One B-rep face of a CAD part: STEP entity #1071.
In plain terms, the planar face has unit normal (1, 0, 0).
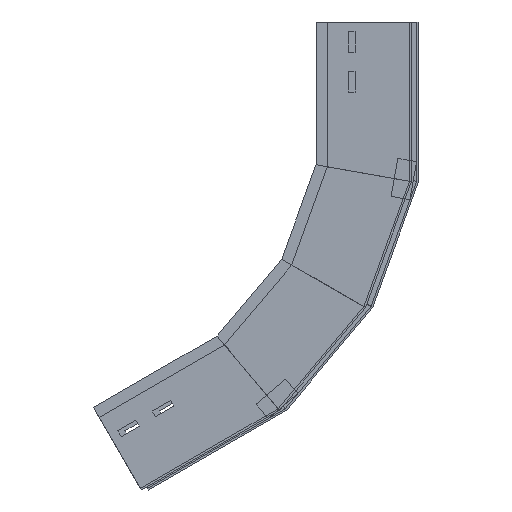
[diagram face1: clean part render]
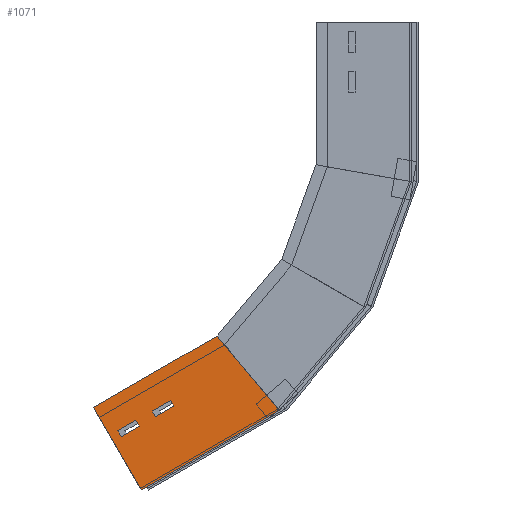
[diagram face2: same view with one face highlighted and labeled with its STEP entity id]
Its self-contained STEP definition (entity closure, numbers rounded to 3 decimals):
#58 = DIRECTION ( 'NONE',  ( 0., 1., 0. ) ) ;
#89 = VERTEX_POINT ( 'NONE', #1633 ) ;
#90 = CARTESIAN_POINT ( 'NONE',  ( 0., 59., -51.505 ) ) ;
#111 = CARTESIAN_POINT ( 'NONE',  ( 0., 59., -51.505 ) ) ;
#126 = CARTESIAN_POINT ( 'NONE',  ( 0., 59., -9.835 ) ) ;
#133 = VECTOR ( 'NONE', #388, 1000. ) ;
#162 = VERTEX_POINT ( 'NONE', #1495 ) ;
#174 = VERTEX_POINT ( 'NONE', #453 ) ;
#176 = EDGE_LOOP ( 'NONE', ( #567, #268, #1676, #1241 ) ) ;
#184 = VERTEX_POINT ( 'NONE', #717 ) ;
#206 = EDGE_CURVE ( 'NONE', #1659, #1650, #1107, .T. ) ;
#216 = CARTESIAN_POINT ( 'NONE',  ( 0., 28.627, -162.352 ) ) ;
#221 = ORIENTED_EDGE ( 'NONE', *, *, #1467, .T. ) ;
#244 = VECTOR ( 'NONE', #1337, 1000. ) ;
#251 = LINE ( 'NONE', #1556, #1500 ) ;
#258 = FACE_OUTER_BOUND ( 'NONE', #339, .T. ) ;
#267 = EDGE_CURVE ( 'NONE', #1477, #358, #1668, .T. ) ;
#268 = ORIENTED_EDGE ( 'NONE', *, *, #1410, .T. ) ;
#337 = EDGE_CURVE ( 'NONE', #184, #162, #1294, .T. ) ;
#339 = EDGE_LOOP ( 'NONE', ( #470, #1189, #221, #1210 ) ) ;
#345 = VECTOR ( 'NONE', #1343, 1000. ) ;
#354 = PLANE ( 'NONE',  #686 ) ;
#356 = CARTESIAN_POINT ( 'NONE',  ( 0., 100., -149.767 ) ) ;
#358 = VERTEX_POINT ( 'NONE', #111 ) ;
#363 = EDGE_CURVE ( 'NONE', #1205, #174, #1523, .T. ) ;
#369 = DIRECTION ( 'NONE',  ( 0., 0., -1. ) ) ;
#388 = DIRECTION ( 'NONE',  ( 0., 0., 1. ) ) ;
#426 = CARTESIAN_POINT ( 'NONE',  ( 0., 66., -51.505 ) ) ;
#453 = CARTESIAN_POINT ( 'NONE',  ( 0., 66., -31.835 ) ) ;
#470 = ORIENTED_EDGE ( 'NONE', *, *, #1238, .F. ) ;
#502 = LINE ( 'NONE', #905, #1010 ) ;
#567 = ORIENTED_EDGE ( 'NONE', *, *, #1621, .T. ) ;
#577 = VECTOR ( 'NONE', #369, 1000. ) ;
#632 = FACE_BOUND ( 'NONE', #176, .T. ) ;
#637 = DIRECTION ( 'NONE',  ( 0., 0., -1. ) ) ;
#643 = CARTESIAN_POINT ( 'NONE',  ( 0., 0., 0. ) ) ;
#651 = CARTESIAN_POINT ( 'NONE',  ( 0., 100., 0. ) ) ;
#663 = DIRECTION ( 'NONE',  ( 0., 1., 0. ) ) ;
#686 = AXIS2_PLACEMENT_3D ( 'NONE', #1536, #893, #1386 ) ;
#717 = CARTESIAN_POINT ( 'NONE',  ( 0., 59., -31.835 ) ) ;
#735 = DIRECTION ( 'NONE',  ( 0., -0.985, -0.174 ) ) ;
#771 = VERTEX_POINT ( 'NONE', #1468 ) ;
#775 = LINE ( 'NONE', #1673, #577 ) ;
#796 = EDGE_CURVE ( 'NONE', #162, #1205, #1585, .T. ) ;
#826 = CARTESIAN_POINT ( 'NONE',  ( 0., 66., -51.505 ) ) ;
#831 = LINE ( 'NONE', #826, #244 ) ;
#893 = DIRECTION ( 'NONE',  ( -1., 0., 0. ) ) ;
#897 = VECTOR ( 'NONE', #1159, 1000. ) ;
#905 = CARTESIAN_POINT ( 'NONE',  ( 0., 66., -73.505 ) ) ;
#921 = CARTESIAN_POINT ( 'NONE',  ( 0., 66., -31.835 ) ) ;
#973 = CARTESIAN_POINT ( 'NONE',  ( 0., 0., 0. ) ) ;
#997 = EDGE_CURVE ( 'NONE', #1441, #89, #1519, .T. ) ;
#1010 = VECTOR ( 'NONE', #1024, 1000. ) ;
#1018 = ORIENTED_EDGE ( 'NONE', *, *, #337, .T. ) ;
#1022 = FACE_BOUND ( 'NONE', #1180, .T. ) ;
#1024 = DIRECTION ( 'NONE',  ( 0., -1., 0. ) ) ;
#1071 = ADVANCED_FACE ( 'NONE', ( #632, #258, #1022 ), #354, .F. ) ;
#1085 = VECTOR ( 'NONE', #637, 1000. ) ;
#1107 = LINE ( 'NONE', #973, #1402 ) ;
#1140 = CARTESIAN_POINT ( 'NONE',  ( 0., 66., -9.835 ) ) ;
#1142 = VECTOR ( 'NONE', #58, 1000. ) ;
#1151 = DIRECTION ( 'NONE',  ( 0., -1., 0. ) ) ;
#1157 = LINE ( 'NONE', #921, #1307 ) ;
#1159 = DIRECTION ( 'NONE',  ( 0., 0., 1. ) ) ;
#1180 = EDGE_LOOP ( 'NONE', ( #1419, #1426, #1246, #1018 ) ) ;
#1189 = ORIENTED_EDGE ( 'NONE', *, *, #206, .F. ) ;
#1205 = VERTEX_POINT ( 'NONE', #1140 ) ;
#1210 = ORIENTED_EDGE ( 'NONE', *, *, #997, .F. ) ;
#1219 = CARTESIAN_POINT ( 'NONE',  ( 0., 66., -9.835 ) ) ;
#1223 = CARTESIAN_POINT ( 'NONE',  ( 0., 59., -73.505 ) ) ;
#1234 = EDGE_CURVE ( 'NONE', #174, #184, #1157, .T. ) ;
#1238 = EDGE_CURVE ( 'NONE', #1650, #1441, #775, .T. ) ;
#1241 = ORIENTED_EDGE ( 'NONE', *, *, #267, .T. ) ;
#1246 = ORIENTED_EDGE ( 'NONE', *, *, #1234, .T. ) ;
#1273 = EDGE_CURVE ( 'NONE', #771, #1477, #502, .T. ) ;
#1294 = LINE ( 'NONE', #126, #133 ) ;
#1307 = VECTOR ( 'NONE', #1151, 1000. ) ;
#1337 = DIRECTION ( 'NONE',  ( 0., 0., -1. ) ) ;
#1343 = DIRECTION ( 'NONE',  ( 0., 0., -1. ) ) ;
#1386 = DIRECTION ( 'NONE',  ( 0., 0., 1. ) ) ;
#1389 = VERTEX_POINT ( 'NONE', #426 ) ;
#1402 = VECTOR ( 'NONE', #1624, 1000. ) ;
#1410 = EDGE_CURVE ( 'NONE', #1389, #771, #831, .T. ) ;
#1417 = CARTESIAN_POINT ( 'NONE',  ( 0., 66., -9.835 ) ) ;
#1419 = ORIENTED_EDGE ( 'NONE', *, *, #796, .T. ) ;
#1426 = ORIENTED_EDGE ( 'NONE', *, *, #363, .T. ) ;
#1435 = VECTOR ( 'NONE', #735, 1000. ) ;
#1441 = VERTEX_POINT ( 'NONE', #356 ) ;
#1467 = EDGE_CURVE ( 'NONE', #1659, #89, #1492, .T. ) ;
#1468 = CARTESIAN_POINT ( 'NONE',  ( 0., 66., -73.505 ) ) ;
#1477 = VERTEX_POINT ( 'NONE', #1223 ) ;
#1492 = LINE ( 'NONE', #1511, #345 ) ;
#1495 = CARTESIAN_POINT ( 'NONE',  ( 0., 59., -9.835 ) ) ;
#1500 = VECTOR ( 'NONE', #663, 1000. ) ;
#1511 = CARTESIAN_POINT ( 'NONE',  ( 0., 0., 0. ) ) ;
#1519 = LINE ( 'NONE', #216, #1435 ) ;
#1523 = LINE ( 'NONE', #1417, #1085 ) ;
#1536 = CARTESIAN_POINT ( 'NONE',  ( 0., 0., 0. ) ) ;
#1556 = CARTESIAN_POINT ( 'NONE',  ( 0., 66., -51.505 ) ) ;
#1585 = LINE ( 'NONE', #1219, #1142 ) ;
#1621 = EDGE_CURVE ( 'NONE', #358, #1389, #251, .T. ) ;
#1624 = DIRECTION ( 'NONE',  ( 0., 1., 0. ) ) ;
#1633 = CARTESIAN_POINT ( 'NONE',  ( 0., 0., -167.4 ) ) ;
#1650 = VERTEX_POINT ( 'NONE', #651 ) ;
#1659 = VERTEX_POINT ( 'NONE', #643 ) ;
#1668 = LINE ( 'NONE', #90, #897 ) ;
#1673 = CARTESIAN_POINT ( 'NONE',  ( 0., 100., 0. ) ) ;
#1676 = ORIENTED_EDGE ( 'NONE', *, *, #1273, .T. ) ;
